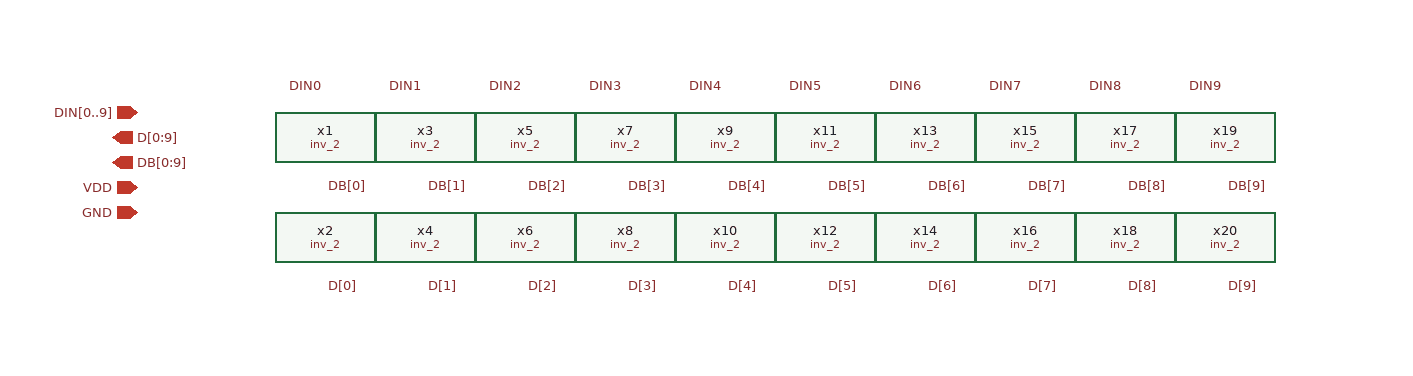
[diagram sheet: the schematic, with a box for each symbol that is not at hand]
v {xschem version=3.4.8RC file_version=1.2}
G {}
K {}
V {}
S {}
E {}
C {sky130_stdcells/inv_2.sym} 270 -350 3 1 {name=x1 VGND=GND VNB=GND VPB=VDD VPWR=VDD prefix=sky130_fd_sc_hd__ }
C {devices/lab_pin.sym} 270 -390 3 1 {name=p3 sig_type=std_logic lab=DIN0}
C {devices/lab_pin.sym} 270 -310 2 0 {name=p1 sig_type=std_logic lab=DB[0]}
C {sky130_stdcells/inv_2.sym} 270 -270 3 1 {name=x2 VGND=GND VNB=GND VPB=VDD VPWR=VDD prefix=sky130_fd_sc_hd__ }
C {devices/lab_pin.sym} 270 -230 2 0 {name=p2 sig_type=std_logic lab=D[0]}
C {sky130_stdcells/inv_2.sym} 350 -350 3 1 {name=x3 VGND=GND VNB=GND VPB=VDD VPWR=VDD prefix=sky130_fd_sc_hd__ }
C {devices/lab_pin.sym} 350 -390 3 1 {name=p4 sig_type=std_logic lab=DIN1}
C {devices/lab_pin.sym} 350 -310 2 0 {name=p5 sig_type=std_logic lab=DB[1]}
C {sky130_stdcells/inv_2.sym} 350 -270 3 1 {name=x4 VGND=GND VNB=GND VPB=VDD VPWR=VDD prefix=sky130_fd_sc_hd__ }
C {devices/lab_pin.sym} 350 -230 2 0 {name=p6 sig_type=std_logic lab=D[1]}
C {sky130_stdcells/inv_2.sym} 430 -350 3 1 {name=x5 VGND=GND VNB=GND VPB=VDD VPWR=VDD prefix=sky130_fd_sc_hd__ }
C {devices/lab_pin.sym} 430 -390 3 1 {name=p7 sig_type=std_logic lab=DIN2}
C {devices/lab_pin.sym} 430 -310 2 0 {name=p8 sig_type=std_logic lab=DB[2]}
C {sky130_stdcells/inv_2.sym} 430 -270 3 1 {name=x6 VGND=GND VNB=GND VPB=VDD VPWR=VDD prefix=sky130_fd_sc_hd__ }
C {devices/lab_pin.sym} 430 -230 2 0 {name=p9 sig_type=std_logic lab=D[2]}
C {sky130_stdcells/inv_2.sym} 510 -350 3 1 {name=x7 VGND=GND VNB=GND VPB=VDD VPWR=VDD prefix=sky130_fd_sc_hd__ }
C {devices/lab_pin.sym} 510 -390 3 1 {name=p10 sig_type=std_logic lab=DIN3}
C {devices/lab_pin.sym} 510 -310 2 0 {name=p11 sig_type=std_logic lab=DB[3]}
C {sky130_stdcells/inv_2.sym} 510 -270 3 1 {name=x8 VGND=GND VNB=GND VPB=VDD VPWR=VDD prefix=sky130_fd_sc_hd__ }
C {devices/lab_pin.sym} 510 -230 2 0 {name=p12 sig_type=std_logic lab=D[3]}
C {sky130_stdcells/inv_2.sym} 590 -350 3 1 {name=x9 VGND=GND VNB=GND VPB=VDD VPWR=VDD prefix=sky130_fd_sc_hd__ }
C {devices/lab_pin.sym} 590 -390 3 1 {name=p13 sig_type=std_logic lab=DIN4}
C {devices/lab_pin.sym} 590 -310 2 0 {name=p14 sig_type=std_logic lab=DB[4]}
C {sky130_stdcells/inv_2.sym} 590 -270 3 1 {name=x10 VGND=GND VNB=GND VPB=VDD VPWR=VDD prefix=sky130_fd_sc_hd__ }
C {devices/lab_pin.sym} 590 -230 2 0 {name=p15 sig_type=std_logic lab=D[4]}
C {sky130_stdcells/inv_2.sym} 670 -350 3 1 {name=x11 VGND=GND VNB=GND VPB=VDD VPWR=VDD prefix=sky130_fd_sc_hd__ }
C {devices/lab_pin.sym} 670 -390 3 1 {name=p16 sig_type=std_logic lab=DIN5}
C {devices/lab_pin.sym} 670 -310 2 0 {name=p17 sig_type=std_logic lab=DB[5]}
C {sky130_stdcells/inv_2.sym} 670 -270 3 1 {name=x12 VGND=GND VNB=GND VPB=VDD VPWR=VDD prefix=sky130_fd_sc_hd__ }
C {devices/lab_pin.sym} 670 -230 2 0 {name=p18 sig_type=std_logic lab=D[5]}
C {sky130_stdcells/inv_2.sym} 750 -350 3 1 {name=x13 VGND=GND VNB=GND VPB=VDD VPWR=VDD prefix=sky130_fd_sc_hd__ }
C {devices/lab_pin.sym} 750 -390 3 1 {name=p19 sig_type=std_logic lab=DIN6}
C {devices/lab_pin.sym} 750 -310 2 0 {name=p20 sig_type=std_logic lab=DB[6]}
C {sky130_stdcells/inv_2.sym} 750 -270 3 1 {name=x14 VGND=GND VNB=GND VPB=VDD VPWR=VDD prefix=sky130_fd_sc_hd__ }
C {devices/lab_pin.sym} 750 -230 2 0 {name=p21 sig_type=std_logic lab=D[6]}
C {sky130_stdcells/inv_2.sym} 830 -350 3 1 {name=x15 VGND=GND VNB=GND VPB=VDD VPWR=VDD prefix=sky130_fd_sc_hd__ }
C {devices/lab_pin.sym} 830 -390 3 1 {name=p22 sig_type=std_logic lab=DIN7}
C {devices/lab_pin.sym} 830 -310 2 0 {name=p23 sig_type=std_logic lab=DB[7]}
C {sky130_stdcells/inv_2.sym} 830 -270 3 1 {name=x16 VGND=GND VNB=GND VPB=VDD VPWR=VDD prefix=sky130_fd_sc_hd__ }
C {devices/lab_pin.sym} 830 -230 2 0 {name=p24 sig_type=std_logic lab=D[7]}
C {sky130_stdcells/inv_2.sym} 910 -350 3 1 {name=x17 VGND=GND VNB=GND VPB=VDD VPWR=VDD prefix=sky130_fd_sc_hd__ }
C {devices/lab_pin.sym} 910 -390 3 1 {name=p25 sig_type=std_logic lab=DIN8}
C {devices/lab_pin.sym} 910 -310 2 0 {name=p26 sig_type=std_logic lab=DB[8]}
C {sky130_stdcells/inv_2.sym} 910 -270 3 1 {name=x18 VGND=GND VNB=GND VPB=VDD VPWR=VDD prefix=sky130_fd_sc_hd__ }
C {devices/lab_pin.sym} 910 -230 2 0 {name=p27 sig_type=std_logic lab=D[8]}
C {sky130_stdcells/inv_2.sym} 990 -350 3 1 {name=x19 VGND=GND VNB=GND VPB=VDD VPWR=VDD prefix=sky130_fd_sc_hd__ }
C {devices/lab_pin.sym} 990 -390 3 1 {name=p28 sig_type=std_logic lab=DIN9}
C {devices/lab_pin.sym} 990 -310 2 0 {name=p29 sig_type=std_logic lab=DB[9]}
C {sky130_stdcells/inv_2.sym} 990 -270 3 1 {name=x20 VGND=GND VNB=GND VPB=VDD VPWR=VDD prefix=sky130_fd_sc_hd__ }
C {devices/lab_pin.sym} 990 -230 2 0 {name=p30 sig_type=std_logic lab=D[9]}
C {devices/title.sym} 160 -40 0 0 {name=l1 author="Yohanes Stefanus"}
C {devices/ipin.sym} 120 -370 0 0 {name=p31 lab=DIN[0..9]}
C {devices/opin.sym} 100 -350 0 0 {name=p32 lab=D[0:9]}
C {devices/opin.sym} 100 -330 0 0 {name=p33 lab=DB[0:9]}
C {devices/ipin.sym} 120 -310 0 0 {name=p34 lab=VDD}
C {devices/ipin.sym} 120 -290 0 0 {name=p35 lab=GND}
